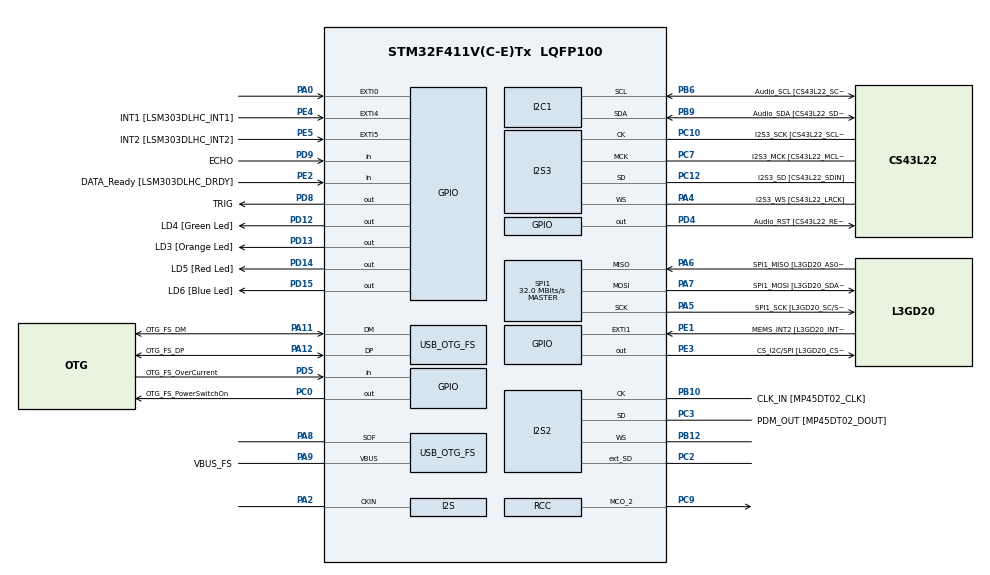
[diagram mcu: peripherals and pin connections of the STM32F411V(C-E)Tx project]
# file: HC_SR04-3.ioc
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I2S2.AudioFreq=I2S_AUDIOFREQ_96K
I2S2.ErrorAudioFreq=0.15 %
I2S2.FullDuplexMode=I2S_FULLDUPLEXMODE_ENABLE
I2S2.Instance=SPI$Index
I2S2.RealAudioFreq=96.153 KHz
I2S2.VirtualMode=I2S_MODE_MASTER
I2S3.AudioFreq=I2S_AUDIOFREQ_96K
I2S3.ErrorAudioFreq=-6.99 %
I2S3.FullDuplexMode=I2S_FULLDUPLEXMODE_DISABLE
I2S3.Instance=SPI$Index
I2S3.RealAudioFreq=89.285 KHz
I2S3.VirtualMode=I2S_MODE_MASTER
Mcu.Family=STM32F4
Mcu.Name=STM32F411V(C-E)Tx
Mcu.Package=LQFP100
NVIC.OTG_FS_IRQn=true\:0\:0\:false\:false\:true\:true\:true
NVIC.PriorityGroup=NVIC_PRIORITYGROUP_0
NVIC.TIM1_UP_TIM10_IRQn=true\:0\:0\:false\:false\:true\:true\:true
PA0-WKUP.GPIO_ModeDefaultEXTI=GPIO_MODE_EVT_RISING
PA0-WKUP.Signal=GPXTI0
PA10.GPIO_Label=OTG_FS_ID
PA10.Signal=USB_OTG_FS_ID
PA11.GPIO_Label=OTG_FS_DM
PA11.Mode=Device_Only
PA11.Signal=USB_OTG_FS_DM
PA12.GPIO_Label=OTG_FS_DP
PA12.Mode=Device_Only
PA12.Signal=USB_OTG_FS_DP
PA13.GPIO_Label=SWDIO
PA13.Mode=Serial_Wire
PA13.Signal=SYS_JTMS-SWDIO
PA14.GPIO_Label=SWCLK
PA14.Mode=Serial_Wire
PA14.Signal=SYS_JTCK-SWCLK
PA2.Mode=Audio_ClockIn
PA2.Signal=I2S_CKIN
PA4.GPIO_Label=I2S3_WS [CS43L22_LRCK]
PA4.GPIO_Mode=GPIO_MODE_AF_PP
PA4.GPIO_PuPd=GPIO_NOPULL
PA4.GPIO_Speed=GPIO_SPEED_FREQ_LOW
PA4.Mode=Half_Duplex_Master
PA4.Signal=I2S3_WS
PA5.GPIO_Label=SPI1_SCK [L3GD20_SC/SPC]
PA5.Mode=Full_Duplex_Master
PA5.Signal=SPI1_SCK
PA6.GPIO_Label=SPI1_MISO [L3GD20_AS0/SDO]
PA6.Mode=Full_Duplex_Master
PA6.Signal=SPI1_MISO
PA7.GPIO_Label=SPI1_MOSI [L3GD20_SDA/SDI/SDO]
PA7.Mode=Full_Duplex_Master
PA7.Signal=SPI1_MOSI
PA8.Mode=Activate_SOF_FS
PA8.Signal=USB_OTG_FS_SOF
PA9.GPIO_Label=VBUS_FS
PA9.Mode=Activate_VBUS
PA9.Signal=USB_OTG_FS_VBUS
PB10.GPIO_Label=CLK_IN [MP45DT02_CLK]
PB10.Mode=Full_Duplex_Master
PB10.Signal=I2S2_CK
PB12.Mode=Full_Duplex_Master
PB12.Signal=I2S2_WS
PB3.GPIO_Label=SWO
PB3.Signal=SYS_JTDO-SWO
PB6.GPIO_Label=Audio_SCL [CS43L22_SCL]
PB6.GPIO_Mode=GPIO_MODE_AF_OD
PB6.GPIO_PuPd=GPIO_NOPULL
PB6.GPIO_Speed=GPIO_SPEED_FREQ_LOW
PB6.Mode=I2C
PB6.Signal=I2C1_SCL
PB9.GPIO_Label=Audio_SDA [CS43L22_SDA]
PB9.GPIO_Mode=GPIO_MODE_AF_OD
PB9.GPIO_PuPd=GPIO_NOPULL
PB9.GPIO_Speed=GPIO_SPEED_FREQ_LOW
PB9.Mode=I2C
PB9.Signal=I2C1_SDA
PC0.GPIO_Label=OTG_FS_PowerSwitchOn
PC0.PinState=GPIO_PIN_SET
PC0.Signal=GPIO_Output
PC10.GPIO_Label=I2S3_SCK [CS43L22_SCLK]
PC10.GPIO_Mode=GPIO_MODE_AF_PP
PC10.GPIO_PuPd=GPIO_NOPULL
PC10.GPIO_Speed=GPIO_SPEED_FREQ_LOW
PC10.Mode=Half_Duplex_Master
PC10.Signal=I2S3_CK
PC12.GPIO_Label=I2S3_SD [CS43L22_SDIN]
PC12.GPIO_Mode=GPIO_MODE_AF_PP
PC12.GPIO_PuPd=GPIO_NOPULL
PC12.GPIO_Speed=GPIO_SPEED_FREQ_LOW
PC12.Mode=Half_Duplex_Master
PC12.Signal=I2S3_SD
PC14-OSC32_IN.GPIO_Label=PC14-OSC32_IN
PC14-OSC32_IN.Mode=LSE-External-Oscillator
PC14-OSC32_IN.Signal=RCC_OSC32_IN
PC15-OSC32_OUT.GPIO_Label=PC15-OSC32_OUT
PC15-OSC32_OUT.Mode=LSE-External-Oscillator
PC15-OSC32_OUT.Signal=RCC_OSC32_OUT
PC2.Mode=Full_Duplex_Master
PC2.Signal=I2S2_ext_SD
PC3.GPIO_Label=PDM_OUT [MP45DT02_DOUT]
PC3.Mode=Full_Duplex_Master
PC3.Signal=I2S2_SD
PC7.GPIO_Label=I2S3_MCK [CS43L22_MCLK]
PC7.GPIO_Mode=GPIO_MODE_AF_PP
PC7.GPIO_PuPd=GPIO_NOPULL
PC7.GPIO_Speed=GPIO_SPEED_FREQ_LOW
PC7.Mode=Master_Clock_Activated
PC7.Signal=I2S3_MCK
PC9.Mode=Clock-out-2
PC9.Signal=RCC_MCO_2
PD12.GPIO_Label=LD4 [Green Led]
PD12.GPIO_PuPd=GPIO_NOPULL
PD12.GPIO_Speed=GPIO_SPEED_FREQ_LOW
PD12.Signal=GPIO_Output
PD13.GPIO_Label=LD3 [Orange Led]
PD13.GPIO_PuPd=GPIO_NOPULL
PD13.GPIO_Speed=GPIO_SPEED_FREQ_LOW
PD13.Signal=GPIO_Output
PD14.GPIO_Label=LD5 [Red Led]
PD14.GPIO_PuPd=GPIO_NOPULL
PD14.GPIO_Speed=GPIO_SPEED_FREQ_LOW
PD14.Signal=GPIO_Output
PD15.GPIO_Label=LD6 [Blue Led]
PD15.GPIO_PuPd=GPIO_NOPULL
PD15.GPIO_Speed=GPIO_SPEED_FREQ_LOW
PD15.Signal=GPIO_Output
PD4.GPIO_Label=Audio_RST [CS43L22_RESET]
PD4.Signal=GPIO_Output
PD5.GPIO_Label=OTG_FS_OverCurrent
PD5.Signal=GPIO_Input
PD8.GPIO_Label=TRIG
PD8.Signal=GPIO_Output
PD9.GPIO_Label=ECHO
PD9.Signal=GPIO_Input
PE1.GPIO_Label=MEMS_INT2 [L3GD20_INT2]
PE1.GPIO_ModeDefaultEXTI=GPIO_MODE_EVT_RISING
PE1.Signal=GPXTI1
PE2.GPIO_Label=DATA_Ready [LSM303DLHC_DRDY]
PE2.Signal=GPIO_Input
PE3.GPIO_Label=CS_I2C/SPI [L3GD20_CS_I2C/SPI]
PE3.Signal=GPIO_Output
PE4.GPIO_Label=INT1 [LSM303DLHC_INT1]
PE4.GPIO_ModeDefaultEXTI=GPIO_MODE_EVT_RISING
PE4.Signal=GPXTI4
PE5.GPIO_Label=INT2 [LSM303DLHC_INT2]
PE5.GPIO_ModeDefaultEXTI=GPIO_MODE_EVT_RISING
PE5.Signal=GPXTI5
PH0\ -\ OSC_IN.GPIO_Label=PH0-OSC_IN
PH0\ -\ OSC_IN.Mode=HSE-External-Oscillator
PH0\ -\ OSC_IN.Signal=RCC_OSC_IN
PH1\ -\ OSC_OUT.GPIO_Label=PH1-OSC_OUT
PH1\ -\ OSC_OUT.Mode=HSE-External-Oscillator
PH1\ -\ OSC_OUT.Signal=RCC_OSC_OUT
ProjectManager.HeapSize=0x200
ProjectManager.StackSize=0x400
ProjectManager.TargetToolchain=STM32CubeIDE
RCC.48MHZClocksFreq_Value=48000000
RCC.AHBFreq_Value=64000000
RCC.APB1CLKDivider=RCC_HCLK_DIV2
RCC.APB1Freq_Value=32000000
RCC.APB1TimFreq_Value=64000000
RCC.APB2Freq_Value=64000000
RCC.APB2TimFreq_Value=64000000
RCC.CortexFreq_Value=64000000
RCC.HCLKFreq_Value=64000000
RCC.HSE_VALUE=8000000
RCC.HSI_VALUE=16000000
RCC.PLLI2SM=5
RCC.PLLI2SN=200
RCC.PLLM=4
RCC.PLLP=RCC_PLLP_DIV6
RCC.PLLQ=8
RCC.SYSCLKFreq_VALUE=64000000
RCC.SYSCLKSource=RCC_SYSCLKSOURCE_PLLCLK
RCC.VCOOutputFreq_Value=384000000
SPI1.BaudRatePrescaler=SPI_BAUDRATEPRESCALER_2
SPI1.CalculateBaudRate=32.0 MBits/s
SPI1.Direction=SPI_DIRECTION_2LINES
SPI1.Mode=SPI_MODE_MASTER
SPI1.VirtualType=VM_MASTER
TIM10.Period=10000
TIM10.Prescaler=63
USB_DEVICE.CLASS_NAME_FS=CDC
USB_DEVICE.VirtualMode=Cdc
USB_DEVICE.VirtualModeFS=Cdc_FS
USB_OTG_FS.VirtualMode=Device_Only
VP_TIM10_VS_ClockSourceINT.Mode=Enable_Timer
VP_USB_DEVICE_VS_USB_DEVICE_CDC_FS.Mode=CDC_FS
board=STM32F411E-DISCO

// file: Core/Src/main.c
/* USER CODE BEGIN Header */
/**
  ******************************************************************************
  * @file           : main.c
  * @brief          : Main program body
  ******************************************************************************
  * @attention
  *
  * <h2><center>&copy; Copyright (c) 2021 STMicroelectronics.
  * All rights reserved.</center></h2>
  *
  * This software component is licensed by ST under Ultimate Liberty license
  * SLA0044, the "License"; You may not use this file except in compliance with
  * the License. You may obtain a copy of the License at:
  *                             www.st.com/SLA0044
  *
  ******************************************************************************
  */
/* USER CODE END Header */
#include "main.h"
#include "usb_device.h"

I2C_HandleTypeDef hi2c1;

I2S_HandleTypeDef hi2s2;
I2S_HandleTypeDef hi2s3;

SPI_HandleTypeDef hspi1;

TIM_HandleTypeDef htim10;

void SystemClock_Config(void);
static void MX_GPIO_Init(void);
static void MX_I2C1_Init(void);
static void MX_I2S2_Init(void);
static void MX_I2S3_Init(void);
static void MX_SPI1_Init(void);
static void MX_TIM10_Init(void);

/* USER CODE BEGIN 0 */
#define LOOP_FREQ (SystemCoreClock/4000000)
#define SystemCoreClockInMHz (SystemCoreClock/1000000)

volatile uint32_t tim10_overflows = 0;

void udelay_asm (uint32_t useconds) {
	   useconds *= LOOP_FREQ;

		  asm volatile("   mov r0, %[useconds]    \n\t"
					   "1: subs r0, #1            \n\t"
					   "   bhi 1b                 \n\t"
					   :
					   : [useconds] "r" (useconds)
					   : "r0");}

//! Вкладених ф-цій в С/С++ немає! Лише за межами інших функцій можна створювати.
//! Саме 10-й таймер!
void TIM10_reinit()
{
  HAL_TIM_Base_Stop(&htim10);
  __HAL_TIM_SET_PRESCALER( &htim10, (SystemCoreClockInMHz-1) );
  __HAL_TIM_SET_COUNTER( &htim10, 0 );
  tim10_overflows = 0;
  HAL_StatusTypeDef i = HAL_TIM_Base_Start_IT(&htim10);
}

uint32_t get_tim10_us()
{
 __HAL_TIM_DISABLE_IT(&htim10, TIM_IT_UPDATE); //! Дуже важливо!
 //__disable_irq();
 uint32_t res = tim10_overflows * 10000 + __HAL_TIM_GET_COUNTER(&htim10);
 //__enable_irq();
 __HAL_TIM_ENABLE_IT(&htim10, TIM_IT_UPDATE); //! Запусаємо саме 10-й таймер!
 return res;
}
/* USER CODE END 0 */

int main(void)
{

  /* MCU Configuration--------------------------------------------------------*/

  /* Reset of all peripherals, Initializes the Flash interface and the Systick. */
  HAL_Init();

  /* Configure the system clock */
  SystemClock_Config();

  /* Initialize all configured peripherals */
  MX_GPIO_Init();
  MX_I2C1_Init();
  MX_I2S2_Init();
  MX_I2S3_Init();
  MX_SPI1_Init();
  MX_USB_DEVICE_Init();
  MX_TIM10_Init();
  /* USER CODE BEGIN 2 */
  TIM10_reinit(); //! Ви її зарано запускали!

  /* USER CODE END 2 */

  /* Infinite loop */
  /* USER CODE BEGIN WHILE */
  char xyz_coords[100];
  HAL_GPIO_WritePin(GPIOD, GPIO_PIN_8, GPIO_PIN_RESET);
  while (1)
	{
	  /* USER CODE END WHILE */

	  /* USER CODE BEGIN 3 */
	int t_state = HAL_GPIO_ReadPin(GPIOD, GPIO_PIN_8);
    while(t_state == GPIO_PIN_SET )
    {
      sprintf(xyz_coords, "Wrong state before triggering, Trig is high\n");
	  CDC_Transmit_FS((uint8_t*)xyz_coords, (uint16_t)strlen(xyz_coords));
	  HAL_Delay(300);
    }
    HAL_GPIO_WritePin(GPIOD, GPIO_PIN_8, GPIO_PIN_SET);
    if ( HAL_GPIO_ReadPin(GPIOD, GPIO_PIN_8) != GPIO_PIN_SET )
    {
      sprintf(xyz_coords, "Line Trig do not went high while triggering.\n");
      CDC_Transmit_FS((uint8_t*)xyz_coords, (uint16_t)strlen(xyz_coords));
      HAL_GPIO_WritePin(TRIG_GPIO_Port, TRIG_Pin, GPIO_PIN_RESET);
      HAL_Delay(300);
      continue;
    }
	udelay_asm(16);
	HAL_GPIO_WritePin(GPIOD, GPIO_PIN_8, GPIO_PIN_RESET);
    if ( HAL_GPIO_ReadPin(GPIOD, GPIO_PIN_8) != GPIO_PIN_RESET )
	{
      sprintf(xyz_coords, "Line Trig do not went low after triggering.\n");
      CDC_Transmit_FS((uint8_t*)xyz_coords, (uint16_t)strlen(xyz_coords));
	  HAL_GPIO_WritePin(GPIOD, GPIO_PIN_8, GPIO_PIN_RESET);
	  HAL_Delay(300);
	  continue;
	}
    if ( HAL_GPIO_ReadPin(GPIOD, GPIO_PIN_9) == GPIO_PIN_SET )
    {
	  sprintf(xyz_coords, "Line ECHO is high too early.\n");
	  CDC_Transmit_FS((uint8_t*)xyz_coords, (uint16_t)strlen(xyz_coords));
	  HAL_Delay(300);
	  continue;
    }

    uint32_t watchdog_begin = get_tim10_us();
    int didnt_had_1_at_echo = 0;

    while(HAL_GPIO_ReadPin(GPIOD, GPIO_PIN_9) == GPIO_PIN_RESET )
    {
	  if( get_tim10_us() - watchdog_begin > 500000 )
	{
	  didnt_had_1_at_echo = 1;
	  break;
	}
    }
    if(didnt_had_1_at_echo)
    {
      sprintf(xyz_coords, "Line ECHO didn't go high for a long time.\n");
      CDC_Transmit_FS((uint8_t*)xyz_coords, (uint16_t)strlen(xyz_coords));
	  HAL_Delay(300);
	  continue;
    }

    uint32_t before = get_tim10_us();
    int didnt_had_0_at_echo = 0;
	while(HAL_GPIO_ReadPin(GPIOD, GPIO_PIN_9) == GPIO_PIN_SET )
	{
	  if( get_tim10_us() - watchdog_begin > 500000 )
	  {
		didnt_had_0_at_echo = 1;
		break;
	  }
	}
	if(didnt_had_0_at_echo)
	{
	  sprintf(xyz_coords, "Line ECHO didn't go low after echoing pulse stared for a long time.\n");
	  CDC_Transmit_FS((uint8_t*)xyz_coords, (uint16_t)strlen(xyz_coords));
	  HAL_Delay(300);
	  continue;
	}
	uint32_t pulse_time = get_tim10_us()-before;
	uint32_t distance = pulse_time/58;
	sprintf(xyz_coords, "Time: %lu us, distance: %lu cm\n",
	   pulse_time,
	   distance
	   );
	CDC_Transmit_FS((uint8_t*)xyz_coords, (uint16_t)strlen(xyz_coords));
	if( distance > 500 )
	{
	  sprintf(xyz_coords, "\tToo far -- possibly no echo at all.");
	  CDC_Transmit_FS((uint8_t*)xyz_coords, (uint16_t)strlen(xyz_coords));
	}
  }

  /* USER CODE END 3 */
}

void SystemClock_Config(void)
{
  RCC_OscInitTypeDef RCC_OscInitStruct = {0};
  RCC_ClkInitTypeDef RCC_ClkInitStruct = {0};
  RCC_PeriphCLKInitTypeDef PeriphClkInitStruct = {0};

  /** Configure the main internal regulator output voltage
  */
  __HAL_RCC_PWR_CLK_ENABLE();
  __HAL_PWR_VOLTAGESCALING_CONFIG(PWR_REGULATOR_VOLTAGE_SCALE1);
  /** Initializes the RCC Oscillators according to the specified parameters
  * in the RCC_OscInitTypeDef structure.
  */
  RCC_OscInitStruct.OscillatorType = RCC_OSCILLATORTYPE_HSE;
  RCC_OscInitStruct.HSEState = RCC_HSE_ON;
  RCC_OscInitStruct.PLL.PLLState = RCC_PLL_ON;
  RCC_OscInitStruct.PLL.PLLSource = RCC_PLLSOURCE_HSE;
  RCC_OscInitStruct.PLL.PLLM = 4;
  RCC_OscInitStruct.PLL.PLLN = 192;
  RCC_OscInitStruct.PLL.PLLP = RCC_PLLP_DIV4;
  RCC_OscInitStruct.PLL.PLLQ = 8;
  if (HAL_RCC_OscConfig(&RCC_OscInitStruct) != HAL_OK)
  {
    Error_Handler();
  }
  /** Initializes the CPU, AHB and APB buses clocks
  */
  RCC_ClkInitStruct.ClockType = RCC_CLOCKTYPE_HCLK|RCC_CLOCKTYPE_SYSCLK
                              |RCC_CLOCKTYPE_PCLK1|RCC_CLOCKTYPE_PCLK2;
  RCC_ClkInitStruct.SYSCLKSource = RCC_SYSCLKSOURCE_PLLCLK;
  RCC_ClkInitStruct.AHBCLKDivider = RCC_SYSCLK_DIV1;
  RCC_ClkInitStruct.APB1CLKDivider = RCC_HCLK_DIV4;
  RCC_ClkInitStruct.APB2CLKDivider = RCC_HCLK_DIV1;

  if (HAL_RCC_ClockConfig(&RCC_ClkInitStruct, FLASH_LATENCY_3) != HAL_OK)
  {
    Error_Handler();
  }
  PeriphClkInitStruct.PeriphClockSelection = RCC_PERIPHCLK_I2S;
  PeriphClkInitStruct.PLLI2S.PLLI2SN = 200;
  PeriphClkInitStruct.PLLI2S.PLLI2SM = 5;
  PeriphClkInitStruct.PLLI2S.PLLI2SR = 2;
  if (HAL_RCCEx_PeriphCLKConfig(&PeriphClkInitStruct) != HAL_OK)
  {
    Error_Handler();
  }
  HAL_RCC_MCOConfig(RCC_MCO2, RCC_MCO2SOURCE_SYSCLK, RCC_MCODIV_1);
}

static void MX_I2C1_Init(void)
{

  hi2c1.Instance = I2C1;
  hi2c1.Init.ClockSpeed = 100000;
  hi2c1.Init.DutyCycle = I2C_DUTYCYCLE_2;
  hi2c1.Init.OwnAddress1 = 0;
  hi2c1.Init.AddressingMode = I2C_ADDRESSINGMODE_7BIT;
  hi2c1.Init.DualAddressMode = I2C_DUALADDRESS_DISABLE;
  hi2c1.Init.OwnAddress2 = 0;
  hi2c1.Init.GeneralCallMode = I2C_GENERALCALL_DISABLE;
  hi2c1.Init.NoStretchMode = I2C_NOSTRETCH_DISABLE;
  if (HAL_I2C_Init(&hi2c1) != HAL_OK)
  {
    Error_Handler();
  }

}

static void MX_I2S2_Init(void)
{

  hi2s2.Instance = SPI2;
  hi2s2.Init.Mode = I2S_MODE_MASTER_TX;
  hi2s2.Init.Standard = I2S_STANDARD_PHILIPS;
  hi2s2.Init.DataFormat = I2S_DATAFORMAT_16B;
  hi2s2.Init.MCLKOutput = I2S_MCLKOUTPUT_DISABLE;
  hi2s2.Init.AudioFreq = I2S_AUDIOFREQ_96K;
  hi2s2.Init.CPOL = I2S_CPOL_LOW;
  hi2s2.Init.ClockSource = I2S_CLOCK_PLL;
  hi2s2.Init.FullDuplexMode = I2S_FULLDUPLEXMODE_ENABLE;
  if (HAL_I2S_Init(&hi2s2) != HAL_OK)
  {
    Error_Handler();
  }

}

static void MX_I2S3_Init(void)
{

  hi2s3.Instance = SPI3;
  hi2s3.Init.Mode = I2S_MODE_MASTER_TX;
  hi2s3.Init.Standard = I2S_STANDARD_PHILIPS;
  hi2s3.Init.DataFormat = I2S_DATAFORMAT_16B;
  hi2s3.Init.MCLKOutput = I2S_MCLKOUTPUT_ENABLE;
  hi2s3.Init.AudioFreq = I2S_AUDIOFREQ_96K;
  hi2s3.Init.CPOL = I2S_CPOL_LOW;
  hi2s3.Init.ClockSource = I2S_CLOCK_PLL;
  hi2s3.Init.FullDuplexMode = I2S_FULLDUPLEXMODE_DISABLE;
  if (HAL_I2S_Init(&hi2s3) != HAL_OK)
  {
    Error_Handler();
  }

}

static void MX_SPI1_Init(void)
{

  /* SPI1 parameter configuration*/
  hspi1.Instance = SPI1;
  hspi1.Init.Mode = SPI_MODE_MASTER;
  hspi1.Init.Direction = SPI_DIRECTION_2LINES;
  hspi1.Init.DataSize = SPI_DATASIZE_8BIT;
  hspi1.Init.CLKPolarity = SPI_POLARITY_LOW;
  hspi1.Init.CLKPhase = SPI_PHASE_1EDGE;
  hspi1.Init.NSS = SPI_NSS_SOFT;
  hspi1.Init.BaudRatePrescaler = SPI_BAUDRATEPRESCALER_2;
  hspi1.Init.FirstBit = SPI_FIRSTBIT_MSB;
  hspi1.Init.TIMode = SPI_TIMODE_DISABLE;
  hspi1.Init.CRCCalculation = SPI_CRCCALCULATION_DISABLE;
  hspi1.Init.CRCPolynomial = 10;
  if (HAL_SPI_Init(&hspi1) != HAL_OK)
  {
    Error_Handler();
  }

}

static void MX_TIM10_Init(void)
{

  htim10.Instance = TIM10;
  htim10.Init.Prescaler = 63;
  htim10.Init.CounterMode = TIM_COUNTERMODE_UP;
  htim10.Init.Period = 10000;
  htim10.Init.ClockDivision = TIM_CLOCKDIVISION_DIV1;
  htim10.Init.AutoReloadPreload = TIM_AUTORELOAD_PRELOAD_DISABLE;
  if (HAL_TIM_Base_Init(&htim10) != HAL_OK)
  {
    Error_Handler();
  }

}

static void MX_GPIO_Init(void)
{
  GPIO_InitTypeDef GPIO_InitStruct = {0};

  /* GPIO Ports Clock Enable */
  __HAL_RCC_GPIOE_CLK_ENABLE();
  __HAL_RCC_GPIOC_CLK_ENABLE();
  __HAL_RCC_GPIOH_CLK_ENABLE();
  __HAL_RCC_GPIOA_CLK_ENABLE();
  __HAL_RCC_GPIOB_CLK_ENABLE();
  __HAL_RCC_GPIOD_CLK_ENABLE();

  /*Configure GPIO pin Output Level */
  HAL_GPIO_WritePin(CS_I2C_SPI_GPIO_Port, CS_I2C_SPI_Pin, GPIO_PIN_RESET);

  /*Configure GPIO pin Output Level */
  HAL_GPIO_WritePin(OTG_FS_PowerSwitchOn_GPIO_Port, OTG_FS_PowerSwitchOn_Pin, GPIO_PIN_SET);

  /*Configure GPIO pin Output Level */
  HAL_GPIO_WritePin(GPIOD, TRIG_Pin|LD4_Pin|LD3_Pin|LD5_Pin
                          |LD6_Pin|Audio_RST_Pin, GPIO_PIN_RESET);

  /*Configure GPIO pin : DATA_Ready_Pin */
  GPIO_InitStruct.Pin = DATA_Ready_Pin;
  GPIO_InitStruct.Mode = GPIO_MODE_INPUT;
  GPIO_InitStruct.Pull = GPIO_NOPULL;
  HAL_GPIO_Init(DATA_Ready_GPIO_Port, &GPIO_InitStruct);

  /*Configure GPIO pin : CS_I2C_SPI_Pin */
  GPIO_InitStruct.Pin = CS_I2C_SPI_Pin;
  GPIO_InitStruct.Mode = GPIO_MODE_OUTPUT_PP;
  GPIO_InitStruct.Pull = GPIO_NOPULL;
  GPIO_InitStruct.Speed = GPIO_SPEED_FREQ_LOW;
  HAL_GPIO_Init(CS_I2C_SPI_GPIO_Port, &GPIO_InitStruct);

  /*Configure GPIO pins : INT1_Pin INT2_Pin MEMS_INT2_Pin */
  GPIO_InitStruct.Pin = INT1_Pin|INT2_Pin|MEMS_INT2_Pin;
  GPIO_InitStruct.Mode = GPIO_MODE_EVT_RISING;
  GPIO_InitStruct.Pull = GPIO_NOPULL;
  HAL_GPIO_Init(GPIOE, &GPIO_InitStruct);

  /*Configure GPIO pin : OTG_FS_PowerSwitchOn_Pin */
  GPIO_InitStruct.Pin = OTG_FS_PowerSwitchOn_Pin;
  GPIO_InitStruct.Mode = GPIO_MODE_OUTPUT_PP;
  GPIO_InitStruct.Pull = GPIO_NOPULL;
  GPIO_InitStruct.Speed = GPIO_SPEED_FREQ_LOW;
  HAL_GPIO_Init(OTG_FS_PowerSwitchOn_GPIO_Port, &GPIO_InitStruct);

  /*Configure GPIO pin : PA0 */
  GPIO_InitStruct.Pin = GPIO_PIN_0;
  GPIO_InitStruct.Mode = GPIO_MODE_EVT_RISING;
  GPIO_InitStruct.Pull = GPIO_NOPULL;
  HAL_GPIO_Init(GPIOA, &GPIO_InitStruct);

  /*Configure GPIO pin : PA2 */
  GPIO_InitStruct.Pin = GPIO_PIN_2;
  GPIO_InitStruct.Mode = GPIO_MODE_AF_PP;
  GPIO_InitStruct.Pull = GPIO_NOPULL;
  GPIO_InitStruct.Speed = GPIO_SPEED_FREQ_LOW;
  GPIO_InitStruct.Alternate = GPIO_AF5_SPI1;
  HAL_GPIO_Init(GPIOA, &GPIO_InitStruct);

  /*Configure GPIO pins : TRIG_Pin LD4_Pin LD3_Pin LD5_Pin
                           LD6_Pin Audio_RST_Pin */
  GPIO_InitStruct.Pin = TRIG_Pin|LD4_Pin|LD3_Pin|LD5_Pin
                          |LD6_Pin|Audio_RST_Pin;
  GPIO_InitStruct.Mode = GPIO_MODE_OUTPUT_PP;
  GPIO_InitStruct.Pull = GPIO_NOPULL;
  GPIO_InitStruct.Speed = GPIO_SPEED_FREQ_LOW;
  HAL_GPIO_Init(GPIOD, &GPIO_InitStruct);

  /*Configure GPIO pins : ECHO_Pin OTG_FS_OverCurrent_Pin */
  GPIO_InitStruct.Pin = ECHO_Pin|OTG_FS_OverCurrent_Pin;
  GPIO_InitStruct.Mode = GPIO_MODE_INPUT;
  GPIO_InitStruct.Pull = GPIO_NOPULL;
  HAL_GPIO_Init(GPIOD, &GPIO_InitStruct);

  /*Configure GPIO pin : PC9 */
  GPIO_InitStruct.Pin = GPIO_PIN_9;
  GPIO_InitStruct.Mode = GPIO_MODE_AF_PP;
  GPIO_InitStruct.Pull = GPIO_NOPULL;
  GPIO_InitStruct.Speed = GPIO_SPEED_FREQ_LOW;
  GPIO_InitStruct.Alternate = GPIO_AF0_MCO;
  HAL_GPIO_Init(GPIOC, &GPIO_InitStruct);

}

/* USER CODE BEGIN 4 */
void HAL_TIM_PeriodElapsedCallback(TIM_HandleTypeDef *htim)
{
	if( htim->Instance == TIM10 )
		tim10_overflows++;
}
/* USER CODE END 4 */

void Error_Handler(void)
{
}

/************************ (C) COPYRIGHT STMicroelectronics *****END OF FILE****/
